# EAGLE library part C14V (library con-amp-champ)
CONNECTOR

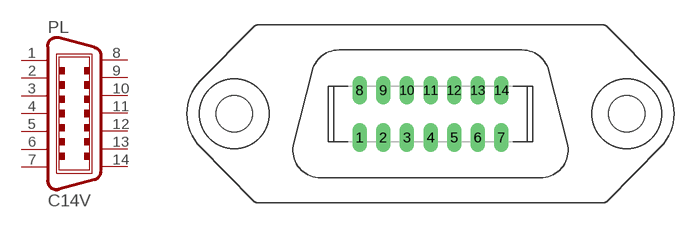
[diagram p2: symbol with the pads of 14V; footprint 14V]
Designator prefix PL

## C14V (OC_FARNELL: unknown; OC_NEWARK: unknown)  [14V]
1  1  pas
2  2  pas
3  3  pas
4  4  pas
5  5  pas
6  6  pas
7  7  pas
8  8  pas
9  9  pas
10  10  pas
11  11  pas
12  12  pas
13  13  pas
14  14  pas

## Footprint 14V (pad centres in mm)
CONNECTOR vertical with mounting hole
drill 0.813 long: 1 -6.477,-2.159; 2 -4.318,-2.159; 3 -2.159,-2.159; 4 0,-2.159; 5 2.159,-2.159; 6 4.318,-2.159; 7 6.477,-2.159; 8 -6.477,2.159; 9 -4.318,2.159; 10 -2.159,2.159; 11 0,2.159; 12 2.159,2.159; 13 4.318,2.159; 14 6.477,2.159
hole 3.302 at -17.932,0
hole 3.302 at 17.932,0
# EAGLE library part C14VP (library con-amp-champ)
CONNECTOR

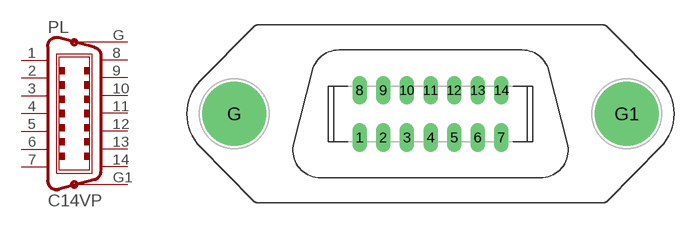
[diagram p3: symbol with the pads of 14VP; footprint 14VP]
Designator prefix PL

## C14VP (OC_FARNELL: unknown; OC_NEWARK: unknown)  [14VP]
1  1  pas
2  2  pas
3  3  pas
4  4  pas
5  5  pas
6  6  pas
7  7  pas
8  8  pas
9  9  pas
10  10  pas
11  11  pas
12  12  pas
13  13  pas
14  14  pas
G  G  pas
G1  G1  pas

## Footprint 14VP (pad centres in mm)
CONNECTOR vertical with mounting pad
drill 0.813 long: 1 -6.477,-2.159; 2 -4.318,-2.159; 3 -2.159,-2.159; 4 0,-2.159; 5 2.159,-2.159; 6 4.318,-2.159; 7 6.477,-2.159; 8 -6.477,2.159; 9 -4.318,2.159; 10 -2.159,2.159; 11 0,2.159; 12 2.159,2.159; 13 4.318,2.159; 14 6.477,2.159
drill 3.302 pad 5.842 round: G -17.932,0; G1 17.932,0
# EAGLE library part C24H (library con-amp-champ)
CONNECTOR

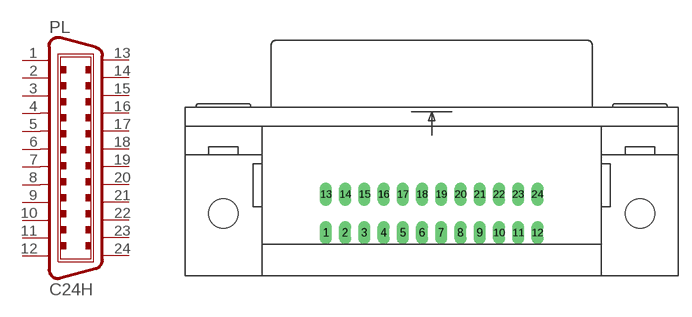
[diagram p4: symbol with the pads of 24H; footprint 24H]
Designator prefix PL

## C24H (OC_FARNELL: unknown; OC_NEWARK: unknown)  [24H]
1  1  pas
2  2  pas
3  3  pas
4  4  pas
5  5  pas
6  6  pas
7  7  pas
8  8  pas
9  9  pas
10  10  pas
11  11  pas
12  12  pas
13  13  pas
14  14  pas
15  15  pas
16  16  pas
17  17  pas
18  18  pas
19  19  pas
20  20  pas
21  21  pas
22  22  pas
23  23  pas
24  24  pas

## Footprint 24H (pad centres in mm)
CONNECTOR horizontal with mounting hole
drill 0.813 long: 1 -11.874,-2.159; 2 -9.716,-2.159; 3 -7.556,-2.159; 4 -5.397,-2.159; 5 -3.239,-2.159; 6 -1.079,-2.159; 7 1.079,-2.159; 8 3.239,-2.159; 9 5.397,-2.159; 10 7.556,-2.159; 11 9.716,-2.159; 12 11.874,-2.159; 13 -11.874,2.159; 14 -9.716,2.159; 15 -7.556,2.159; 16 -5.397,2.159; 17 -3.239,2.159; 18 -1.079,2.159; 19 1.079,2.159; 20 3.239,2.159; 21 5.397,2.159; 22 7.556,2.159; 23 9.716,2.159; 24 11.874,2.159
hole 3.302 at -23.393,0
hole 3.302 at 23.393,0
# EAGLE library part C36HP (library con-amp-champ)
CONNECTOR

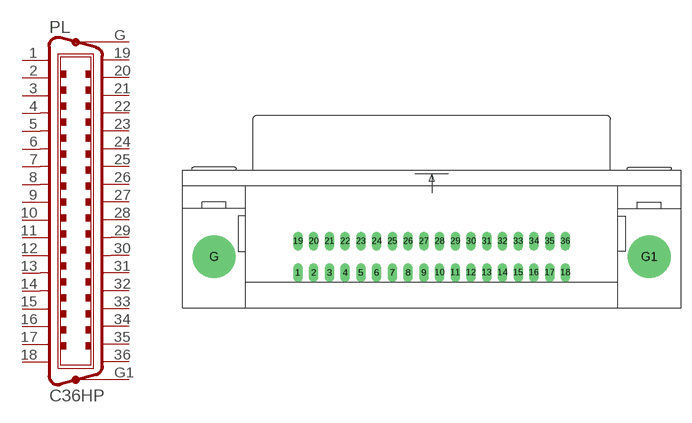
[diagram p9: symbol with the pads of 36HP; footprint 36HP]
Designator prefix PL

## C36HP (OC_FARNELL: unknown; OC_NEWARK: unknown)  [36HP]
1  1  pas
2  2  pas
3  3  pas
4  4  pas
5  5  pas
6  6  pas
7  7  pas
8  8  pas
9  9  pas
10  10  pas
11  11  pas
12  12  pas
13  13  pas
14  14  pas
15  15  pas
16  16  pas
17  17  pas
18  18  pas
19  19  pas
20  20  pas
21  21  pas
22  22  pas
23  23  pas
24  24  pas
25  25  pas
26  26  pas
27  27  pas
28  28  pas
29  29  pas
30  30  pas
31  31  pas
32  32  pas
33  33  pas
34  34  pas
35  35  pas
36  36  pas
G  G  pas
G1  G1  pas

## Footprint 36HP (pad centres in mm)
CONNECTOR horizontal with mounting pad
drill 0.813 long: 1 -18.352,-2.159; 2 -16.192,-2.159; 3 -14.034,-2.159; 4 -11.874,-2.159; 5 -9.716,-2.159; 6 -7.556,-2.159; 7 -5.397,-2.159; 8 -3.239,-2.159; 9 -1.079,-2.159; 10 1.079,-2.159; 11 3.239,-2.159; 12 5.397,-2.159; 13 7.556,-2.159; 14 9.716,-2.159; 15 11.874,-2.159; 16 14.034,-2.159; 17 16.192,-2.159; 18 18.352,-2.159; 19 -18.352,2.159; 20 -16.192,2.159; 21 -14.034,2.159; 22 -11.874,2.159; 23 -9.716,2.159; 24 -7.556,2.159; 25 -5.397,2.159; 26 -3.239,2.159; 27 -1.079,2.159; 28 1.079,2.159; 29 3.239,2.159; 30 5.397,2.159; 31 7.556,2.159; 32 9.716,2.159; 33 11.874,2.159; 34 14.034,2.159; 35 16.192,2.159; 36 18.352,2.159
drill 3.302 pad 5.842 round: G -29.87,0; G1 29.87,0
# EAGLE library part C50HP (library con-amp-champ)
CONNECTOR

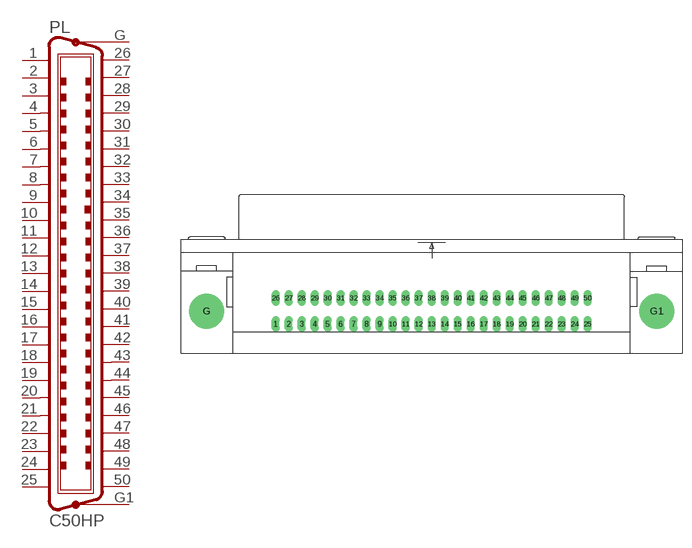
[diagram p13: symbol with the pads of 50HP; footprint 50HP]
Designator prefix PL

## C50HP (OC_FARNELL: unknown; OC_NEWARK: unknown)  [50HP]
1  1  pas
2  2  pas
3  3  pas
4  4  pas
5  5  pas
6  6  pas
7  7  pas
8  8  pas
9  9  pas
10  10  pas
11  11  pas
12  12  pas
13  13  pas
14  14  pas
15  15  pas
16  16  pas
17  17  pas
18  18  pas
19  19  pas
20  20  pas
21  21  pas
22  22  pas
23  23  pas
24  24  pas
25  25  pas
26  26  pas
27  27  pas
28  28  pas
29  29  pas
30  30  pas
31  31  pas
32  32  pas
33  33  pas
34  34  pas
35  35  pas
36  36  pas
37  37  pas
38  38  pas
39  39  pas
40  40  pas
41  41  pas
42  42  pas
43  43  pas
44  44  pas
45  45  pas
46  46  pas
47  47  pas
48  48  pas
49  49  pas
50  50  pas
G  G  pas
G1  G1  pas

## Footprint 50HP (pad centres in mm)
CONNECTOR horizontal with mounting pad
drill 0.813 long: 1 -25.908,-2.159; 2 -23.749,-2.159; 3 -21.59,-2.159; 4 -19.431,-2.159; 5 -17.272,-2.159; 6 -15.113,-2.159; 7 -12.954,-2.159; 8 -10.795,-2.159; 9 -8.636,-2.159; 10 -6.477,-2.159; 11 -4.318,-2.159; 12 -2.159,-2.159; 13 0,-2.159; 14 2.159,-2.159; 15 4.318,-2.159; 16 6.477,-2.159; 17 8.636,-2.159; 18 10.795,-2.159; 19 12.954,-2.159; 20 15.113,-2.159; 21 17.272,-2.159; 22 19.431,-2.159; 23 21.59,-2.159; 24 23.749,-2.159; 25 25.908,-2.159; 26 -25.908,2.159; 27 -23.749,2.159; 28 -21.59,2.159; 29 -19.431,2.159; 30 -17.272,2.159; 31 -15.113,2.159; 32 -12.954,2.159; 33 -10.795,2.159; 34 -8.636,2.159; 35 -6.477,2.159; 36 -4.318,2.159; 37 -2.159,2.159; 38 0,2.159; 39 2.159,2.159; 40 4.318,2.159; 41 6.477,2.159; 42 8.636,2.159; 43 10.795,2.159; 44 12.954,2.159; 45 15.113,2.159; 46 17.272,2.159; 47 19.431,2.159; 48 21.59,2.159; 49 23.749,2.159; 50 25.908,2.159
drill 3.302 pad 5.842 round: G -37.363,0; G1 37.363,0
